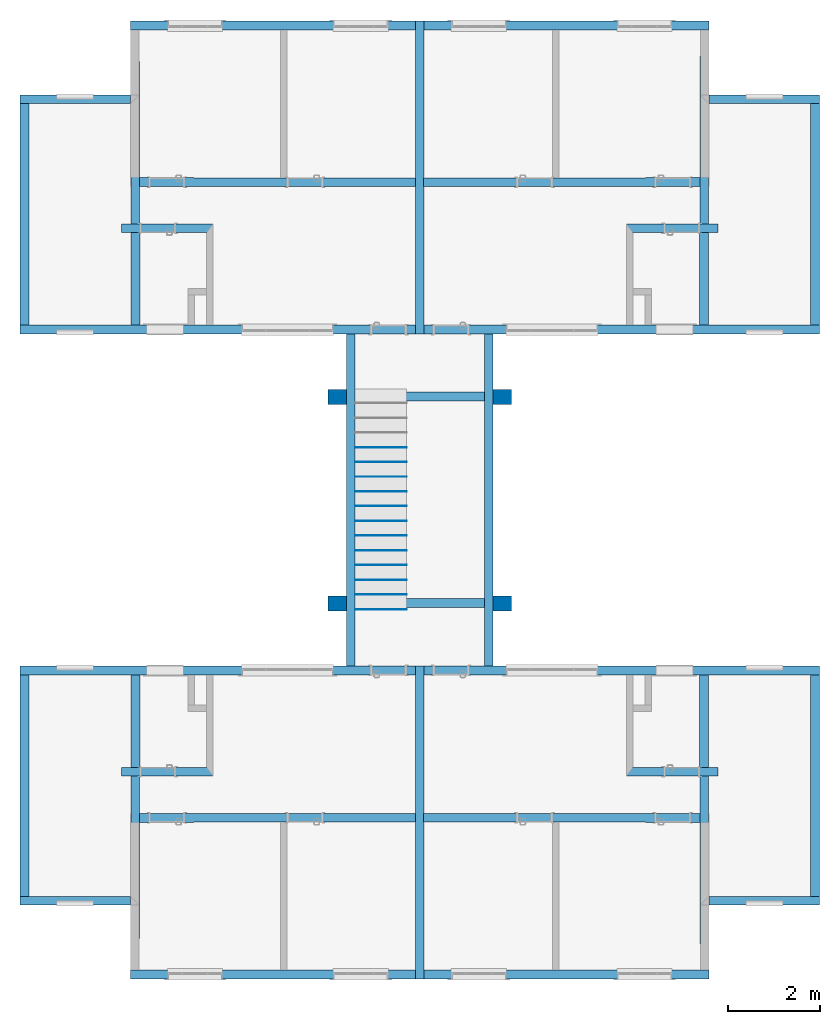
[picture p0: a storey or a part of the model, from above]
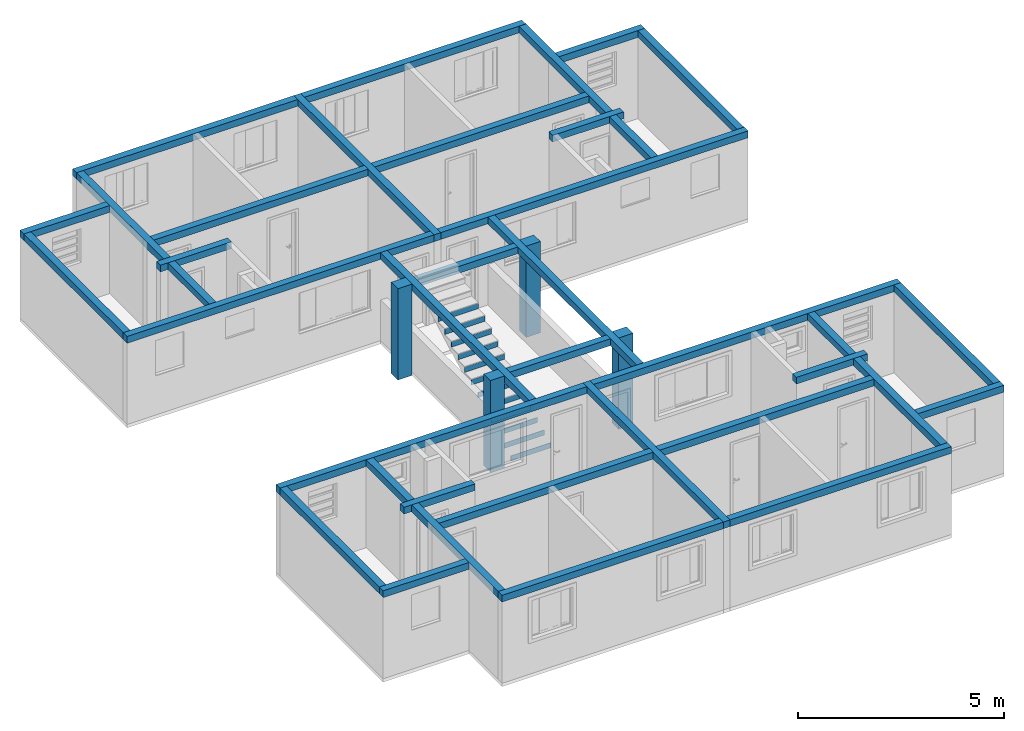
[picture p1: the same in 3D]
Properties of the parts of a building model (IFC2X3)

# File
Description: ViewDefinition [CoordinationView_V2.0, QuantityTakeOffAddOnView], Option [Elements to export: All elements on Current Story], Option [Partial Structure Display: Entire Model], Option [IFC Domain: All], Option [Structural Function: All Elements], Option [Convert Grid elements: On], Option [Convert IFC Annotations and Archicad 2D elements: Off], Option [Convert 2D symbols of Doors and Windows: Off], Option [Export geometries that Participates in Collision Detection only: Off], Option [Split complex elements: Off], Option [Material Preservation: Explode where necessary], Option [Elements in Solid Element Operations: Extruded/revolved], Option [Elements with junctions: Extruded/revolved without junctions], Option [IFC Model position: Survey Point and Project Origin], Option [Curtain Wall export mode: Container Element], Option [Railing export mode: Single Element], Option [Stair export mode: Container Element], Option [Properties To Export: All properties], Option [Space containment: Off], Option [Geometry to type objects: Off], Option [Element Properties: Visible Only], Option [Building Material Properties: Off], Option [Element Parameters: Off], Option [Component Parameters: All], Option [IFC Base Quantities: On], Option [Door Window Parameters: On], Option [IFC Space boundaries: Off], Option [Archicad Zone Categories as IFC Space classification data: Off], Option [Element Classifications: On]
File name: C:\Users\jplen\Downloads\Modelagem - Pavimento tipo (Plus).ifc
Time: 2024-05-23T11:48:52
Author: Architect
Organization: Building Designer Office
Written by: DDS_IFC v3.0
Made in: IFC file generated by Graphisoft Archicad 27.0.0 BRA FULL Windows version (IFC add-on version: 3001 BRA FULL).
Authorization: The authorising person

# IfcSite, Local
RefLatitude: -23, -32, 0, 0; RefLongitude: -46, -38, 0, 0; RefElevation: 0 mm
BaseQuantities - GrossPerimeter: 0 mm; GrossArea: 0 m2

# IfcBuilding, Construção
BaseQuantities - GrossFloorArea: 244.261 m2

# IfcBuildingStorey, Pavimento Tipo
In: Construção
Elevation: 0 mm
BaseQuantities - NetHeight: 2600 mm; GrossHeight: 2600 mm; Height: 2600 mm; GrossFloorArea: 244.261 m2

# IfcSpace: Circulação (2)
In: Pavimento Tipo
Type - ElementType: EXTERNAL; PredefinedType: USERDEFINED
InteriorOrExteriorSpace: INTERNAL
AC_Pset_RenovationAndPhasing - Renovation Status: Existing
BaseQuantities - Height: 2600 mm; FinishCeilingHeight: 2600 mm; FinishFloorHeight: 0 mm; ClearHeight: 2600 mm
Pset_SpaceCommon - Category: Circulação
Name | LongName | Classification | GrossFloorArea (m2) = NetFloorArea (m2) = SpaceNetFloorAreaBOMA (m2) = SpaceUsableFloorAreaBOMA (m2) = GrossCeilingArea (m2) = NetCeilingArea (m2) | GrossWallArea (m2) | NetWallArea (m2) | GrossPerimeter (mm) = NetPerimeter (mm) | GrossVolume (m3) = NetVolume (m3)
09 | Caixa de escada | Espaço Externo (Classificação Archicad); 4A 16 01 04 Escada (NBR 15965-6 4A) | 5.376 | 5.76 | 5.76 | 11840 | 13.9776
10 | Circulação Horizontal Externa | Espaço Externo (Classificação Archicad); 4A 16 04 04 Saguão (NBR 15965-6 4A) | 14.8841 | 25.032 | 18.312 | 22280 | 38.6987

# IfcSpace: Circulação (4)
In: Pavimento Tipo
Type - ElementType: INTERNAL; PredefinedType: USERDEFINED
LongName: Circulação; InteriorOrExteriorSpace: INTERNAL; Classification: Espaço Residencial (Classificação Archicad); 4A 19 04 10 Circulação (NBR 15965-6 4A)
Pset_SpaceCommon - Category: Circulação
AC_Pset_RenovationAndPhasing - Renovation Status: Existing
BaseQuantities - Height: 2600 mm; FinishCeilingHeight: 2600 mm; FinishFloorHeight: 0 mm; ClearHeight: 2600 mm; GrossFloorArea: 1.4565 m2; NetFloorArea: 1.4565 m2; SpaceNetFloorAreaBOMA: 1.4565 m2; SpaceUsableFloorAreaBOMA: 1.4565 m2; GrossCeilingArea: 1.4565 m2; NetCeilingArea: 1.4565 m2; GrossWallArea: 4.29812 m2; NetWallArea: 2.61812 m2; GrossPerimeter: 5209.26 mm; NetPerimeter: 5209.26 mm; GrossVolume: 3.7869 m3; NetVolume: 3.78689 m3
Name
Apartamento 1 - 13
Apartamento 2 - 13
Apartamento 3 - 13
Apartamento 4 - 13

# IfcSpace: Área privativa (4)
In: Pavimento Tipo
LongName: Banheiro; InteriorOrExteriorSpace: INTERNAL; Classification: 4A 19 04 07 Banheiro residencial (NBR 15965-6 4A)
Pset_SpaceCommon - Category: Área privativa
AC_Pset_RenovationAndPhasing - Renovation Status: Existing
BaseQuantities - Height: 2600 mm; FinishCeilingHeight: 2600 mm; FinishFloorHeight: 0 mm; ClearHeight: 2600 mm; GrossFloorArea: 2.6146 m2; NetFloorArea: 2.6146 m2; SpaceNetFloorAreaBOMA: 2.6146 m2; SpaceUsableFloorAreaBOMA: 2.6146 m2; GrossCeilingArea: 2.6146 m2; NetCeilingArea: 2.6146 m2; GrossWallArea: 12.3731 m2; NetWallArea: 10.2131 m2; GrossPerimeter: 6940 mm; NetPerimeter: 6940 mm; GrossVolume: 6.79796 m3; NetVolume: 6.79796 m3
Name
Apartamento 1 - 06
Apartamento 2 - 06
Apartamento 3 - 06
Apartamento 4 - 06

# IfcSpace: Área privativa (16)
In: Pavimento Tipo
Type - ElementType: INTERNAL; PredefinedType: USERDEFINED
InteriorOrExteriorSpace: INTERNAL
Pset_SpaceCommon - Category: Área privativa
AC_Pset_RenovationAndPhasing - Renovation Status: Existing
BaseQuantities - Height: 2600 mm; FinishCeilingHeight: 2600 mm; FinishFloorHeight: 0 mm; ClearHeight: 2600 mm
Name | LongName | Classification | GrossFloorArea (m2) = NetFloorArea (m2) = SpaceNetFloorAreaBOMA (m2) = SpaceUsableFloorAreaBOMA (m2) = GrossCeilingArea (m2) = NetCeilingArea (m2) | GrossWallArea (m2) | NetWallArea (m2) | GrossPerimeter (mm) = NetPerimeter (mm) | GrossVolume (m3) = NetVolume (m3)
Apartamento 1 - 12 | Sala de estar | Espaço Residencial (Classificação Archicad); 4A 19 01 07 Sala de Estar (NBR 15965-6 4A) | 13.2704 | 26.7962 | 21.0362 | 14836.1 | 34.5031
Apartamento 1 - 04 | Quarto 01 | 4A 19 01 01 Dormitório (NBR 15965-6 4A); Espaço Residencial (Classificação Archicad) | 8.96458 | 21.7672 | 18.6681 | 12005.8 | 23.3079
Apartamento 1 - 14 | Cozinha | Espaço Residencial (Classificação Archicad); 4A 19 01 25 Cozinha (NBR 15965-6 4A) | 10.5869 | 23.5579 | 21.9579 | 14435.8 | 27.5258
Apartamento 1 - 05 | Quarto 02 | 4A 19 01 01 Dormitório (NBR 15965-6 4A); Espaço Residencial (Classificação Archicad) | 9.85631 | 31.74 | 28.62 | 12941 | 25.6264
Apartamento 2 - 12 | Sala de estar | Espaço Residencial (Classificação Archicad); 4A 19 01 07 Sala de Estar (NBR 15965-6 4A) | 13.2704 | 26.7962 | 21.0362 | 14836.1 | 34.5031
Apartamento 2 - 04 | Quarto 01 | 4A 19 01 01 Dormitório (NBR 15965-6 4A); Espaço Residencial (Classificação Archicad) | 8.96458 | 21.7672 | 18.6681 | 12005.8 | 23.3079
Apartamento 2 - 05 | Quarto 02 | 4A 19 01 01 Dormitório (NBR 15965-6 4A); Espaço Residencial (Classificação Archicad) | 9.85631 | 31.702 | 28.582 | 12941 | 25.6264
Apartamento 2 - 14 | Cozinha | Espaço Residencial (Classificação Archicad); 4A 19 01 25 Cozinha (NBR 15965-6 4A) | 10.5869 | 23.5579 | 21.9579 | 14435.8 | 27.5258
Apartamento 3 - 12 | Sala de estar | Espaço Residencial (Classificação Archicad); 4A 19 01 07 Sala de Estar (NBR 15965-6 4A) | 13.2704 | 26.7962 | 21.0362 | 14836.1 | 34.5031
Apartamento 3 - 04 | Quarto 01 | 4A 19 01 01 Dormitório (NBR 15965-6 4A); Espaço Residencial (Classificação Archicad) | 8.96458 | 21.7672 | 18.6681 | 12005.8 | 23.3079
Apartamento 3 - 14 | Cozinha | Espaço Residencial (Classificação Archicad); 4A 19 01 25 Cozinha (NBR 15965-6 4A) | 10.5869 | 23.5579 | 21.9579 | 14435.8 | 27.5258
Apartamento 3 - 05 | Quarto 02 | 4A 19 01 01 Dormitório (NBR 15965-6 4A); Espaço Residencial (Classificação Archicad) | 9.85631 | 31.74 | 28.62 | 12941 | 25.6264
Apartamento 4 - 12 | Sala de estar | Espaço Residencial (Classificação Archicad); 4A 19 01 07 Sala de Estar (NBR 15965-6 4A) | 13.2704 | 26.7962 | 21.0362 | 14836.1 | 34.5031
Apartamento 4 - 04 | Quarto 01 | 4A 19 01 01 Dormitório (NBR 15965-6 4A); Espaço Residencial (Classificação Archicad) | 8.96458 | 21.7672 | 18.6681 | 12005.8 | 23.3079
Apartamento 4 - 14 | Cozinha | Espaço Residencial (Classificação Archicad); 4A 19 01 25 Cozinha (NBR 15965-6 4A) | 10.5869 | 23.5579 | 21.9579 | 14435.8 | 27.5258
Apartamento 4 - 05 | Quarto 02 | 4A 19 01 01 Dormitório (NBR 15965-6 4A); Espaço Residencial (Classificação Archicad) | 9.85631 | 31.702 | 28.582 | 12941 | 25.6264

# IfcSpace: Área técnica (4)
In: Pavimento Tipo
Type - ElementType: INTERNAL; PredefinedType: USERDEFINED
LongName: Shaft do banheiro; InteriorOrExteriorSpace: INTERNAL; Classification: Espaço Residencial (Classificação Archicad); 4A 13 01 13 22 Shaft de Distribuição de Hidráulica (NBR 15965-6 4A)
Pset_SpaceCommon - Category: Área técnica
AC_Pset_RenovationAndPhasing - Renovation Status: Existing
BaseQuantities - Height: 2600 mm; FinishCeilingHeight: 2600 mm; FinishFloorHeight: 0 mm; ClearHeight: 2600 mm; GrossFloorArea: 0.1716 m2; NetFloorArea: 0.1716 m2; SpaceNetFloorAreaBOMA: 0.1716 m2; SpaceUsableFloorAreaBOMA: 0.1716 m2; GrossCeilingArea: 0.1716 m2; NetCeilingArea: 0.1716 m2; GrossWallArea: 4.732 m2; NetWallArea: 4.732 m2; GrossPerimeter: 1840 mm; NetPerimeter: 1840 mm; GrossVolume: 0.44616 m3; NetVolume: 0.44616 m3
Name
Apartamento 1 - 11
Apartamento 2 - 11
Apartamento 3 - 11
Apartamento 4 - 11

# IfcBeam: Concreto - Estrutural 190 x 200 (38)
In: Pavimento Tipo
Type - PredefinedType: BEAM
Classification: 3E 12 06 02 00 Viga (NBR 15965-5 3E); Viga (Classificação Archicad); Material: Concreto - Estrutural
Pset_ManufacturerTypeInformation - ProductionYear: DD/MM/YYYY
Pset_BeamCommon - LoadBearing: yes; Reference: Concreto - Estrutural 190 x 200
Component Properties - Concreto - Estrutural, Tipo de Componente: Núcleo
AC_Pset_RenovationAndPhasing - Renovation Status: Existing
BaseQuantities - Width: 190 mm; Depth: 200 mm; CrossSectionArea: 0.038 m2
Component Quantities - Concreto - Estrutural, Espessura do Componente: 190 mm; Concreto - Estrutural, Altura do Componente Retangular: 200 mm; Concreto - Estrutural, Largura do Componente Retangular: 190 mm; Concreto - Estrutural, Área de Seção Transversal do Componente: 0.038 m2
Name | Description | IsExternal | Concreto - Estrutural, Carbono Incorporado | Concreto - Estrutural, Energia Incorporada (MJ) | NetSurfaceAreaExtrudedSides (m2) = OuterSurfaceArea (m2) | Length (mm) | TotalSurfaceArea (m2) = GrossSurfaceArea (m2) = NetSurfaceArea (m2) | GrossVolume (m3) | NetVolume (m3) = Concreto - Estrutural, Volume Componente (Líquido) (m3) = Concreto - Estrutural, Volume do componente (Bruto) (m3) = Concreto - Estrutural, Volume Componente (Condicional) (m3) | Concreto - Estrutural, Massa (kg) | Concreto - Estrutural, Área de Componente Projetada (Líquida) (m2) = Concreto - Estrutural, Área de Componente Projetada (Bruta) (m2)
Apartamento 1 - V03 | Viga-externa-inloco-concreto_armado-19cm x 20cm | yes | 41.4885 (kgCO₂) | 402.313 | 1.87002 | 2397.46 | 1.94602 | 0.0911034 | 0.0911034 | 209.538 | 0.479492
Apartamento 1 - V01 | Viga-externa-inloco-concreto_armado-19cm x 20cm | yes | 148.568 (kgCO₂) | 1440.66 | 6.69645 | 8585.19 | 6.77245 | 0.333457 | 0.326237 | 750.346 | 1.71704
Apartamento 1 - V05 | Viga-externa-inloco-concreto_armado-19cm x 20cm | yes | 107.073 (kgCO₂) | 1038.28 | 4.82612 | 6187.33 | 4.90212 | 0.242339 | 0.235119 | 540.773 | 1.23747
Apartamento 1 - V04 | Viga-externa-inloco-concreto_armado-19cm x 20cm | yes | 72.9091 (kgCO₂) | 706.997 | 3.32416 | 4403.36 | 3.40016 | 0.174531 | 0.160099 | 368.228 | 0.880671
Apartamento 1 - V08 | Viga-interna-inloco-concreto_armado-19cm x 20cm | no | 34.4373 (kgCO₂) | 333.938 | 1.5522 | 1990 | 1.6282 | 0.07562 | 0.07562 | 173.926 | 0.398
Apartamento 1 - V02 | Viga-externa-inloco-concreto_armado-19cm x 20cm | yes | 83.238 (kgCO₂) | 807.156 | 3.7518 | 4810 | 3.8278 | 0.19 | 0.18278 | 420.394 | 0.962
Apartamento 1 - V09 | Viga-interna-inloco-concreto_armado-19cm x 20cm | no | 34.7834 (kgCO₂) | 337.294 | 1.5678 | 2010 | 1.6438 | 0.0836 | 0.07638 | 175.674 | 0.402
Apartamento 1 - V07 | Viga-interna-inloco-concreto_armado-19cm x 20cm | no | 103.652 (kgCO₂) | 1005.11 | 4.67194 | 5989.94 | 4.74794 | 0.228153 | 0.227607 | 523.497 | 1.19799
Apartamentos 1 e 2 - V06 | Viga-interna-inloco-concreto_armado-19cm x 20cm |  | 117.413 (kgCO₂) | 1138.55 | 5.25739 | 6792.9 | 5.33339 | 0.25813 | 0.257823 | 592.993 | 1.35858
Apartamento 2 - V03 | Viga-externa-inloco-concreto_armado-19cm x 20cm | yes | 41.4885 (kgCO₂) | 402.313 | 1.87002 | 2397.46 | 1.94602 | 0.0911034 | 0.0911034 | 209.538 | 0.479492
Apartamento 2 - V05 | Viga-externa-inloco-concreto_armado-19cm x 20cm | yes | 107.073 (kgCO₂) | 1038.28 | 4.82612 | 6187.33 | 4.90212 | 0.235119 | 0.235119 | 540.773 | 1.23747
Apartamento 2 - V01 | Viga-externa-inloco-concreto_armado-19cm x 20cm | yes | 148.568 (kgCO₂) | 1440.66 | 6.69645 | 8585.19 | 6.77245 | 0.326237 | 0.326237 | 750.346 | 1.71704
Apartamento 2 - V04 | Viga-externa-inloco-concreto_armado-19cm x 20cm | yes | 72.9091 (kgCO₂) | 706.997 | 3.32416 | 4403.36 | 3.40016 | 0.174531 | 0.160099 | 368.228 | 0.880671
Apartamento 2 - V09 | Viga-interna-inloco-concreto_armado-19cm x 20cm | no | 34.7834 (kgCO₂) | 337.294 | 1.5678 | 2010 | 1.6438 | 0.0836 | 0.07638 | 175.674 | 0.402
Apartamento 2 - V02 | Viga-externa-inloco-concreto_armado-19cm x 20cm | yes | 83.238 (kgCO₂) | 807.156 | 3.7518 | 4810 | 3.8278 | 0.19 | 0.18278 | 420.394 | 0.962
Apartamento 2 - V07 | Viga-interna-inloco-concreto_armado-19cm x 20cm | no | 103.792 (kgCO₂) | 1006.47 | 4.67824 | 5998 | 4.75424 | 0.228153 | 0.227914 | 524.203 | 1.1996
Apartamento 4 - V02 | Viga-externa-inloco-concreto_armado-19cm x 20cm | yes | 83.238 (kgCO₂) | 807.156 | 3.7518 | 4810 | 3.8278 | 0.19 | 0.18278 | 420.394 | 0.962
Apartamento 4 - V09 | Viga-interna-inloco-concreto_armado-19cm x 20cm | no | 34.7834 (kgCO₂) | 337.294 | 1.5678 | 2010 | 1.6438 | 0.0836 | 0.07638 | 175.674 | 0.402
Apartamento 4 - V08 | Viga-interna-inloco-concreto_armado-19cm x 20cm | no | 34.4373 (kgCO₂) | 333.938 | 1.5522 | 1990 | 1.6282 | 0.07562 | 0.07562 | 173.926 | 0.398
Apartamento 4 - V07 | Viga-interna-inloco-concreto_armado-19cm x 20cm | no | 103.792 (kgCO₂) | 1006.47 | 4.67824 | 5998 | 4.75424 | 0.228153 | 0.227914 | 524.203 | 1.1996
Apartamento 2 - V08 | Viga-interna-inloco-concreto_armado-19cm x 20cm | no | 34.4373 (kgCO₂) | 333.938 | 1.5522 | 1990 | 1.6282 | 0.07562 | 0.07562 | 173.926 | 0.398
Apartamento 3 - V03 | Viga-externa-inloco-concreto_armado-19cm x 20cm | yes | 41.4885 (kgCO₂) | 402.313 | 1.87002 | 2397.46 | 1.94602 | 0.0911034 | 0.0911034 | 209.538 | 0.479492
Apartamento 3 - V01 | Viga-externa-inloco-concreto_armado-19cm x 20cm | yes | 148.568 (kgCO₂) | 1440.66 | 6.69645 | 8585.19 | 6.77245 | 0.333457 | 0.326237 | 750.346 | 1.71704
Apartamento 3 - V05 | Viga-externa-inloco-concreto_armado-19cm x 20cm | yes | 107.073 (kgCO₂) | 1038.28 | 4.82612 | 6187.33 | 4.90212 | 0.242339 | 0.235119 | 540.773 | 1.23747
Apartamento 3 - V08 | Viga-interna-inloco-concreto_armado-19cm x 20cm | no | 34.4373 (kgCO₂) | 333.938 | 1.5522 | 1990 | 1.6282 | 0.07562 | 0.07562 | 173.926 | 0.398
Apartamento 3 - V02 | Viga-externa-inloco-concreto_armado-19cm x 20cm | yes | 83.238 (kgCO₂) | 807.156 | 3.7518 | 4810 | 3.8278 | 0.19 | 0.18278 | 420.394 | 0.962
Apartamento 3 - V09 | Viga-interna-inloco-concreto_armado-19cm x 20cm | no | 34.7834 (kgCO₂) | 337.294 | 1.5678 | 2010 | 1.6438 | 0.0836 | 0.07638 | 175.674 | 0.402
Apartamento 3 - V04 | Viga-externa-inloco-concreto_armado-19cm x 20cm | yes | 72.9091 (kgCO₂) | 706.997 | 3.32416 | 4403.36 | 3.40016 | 0.174531 | 0.160099 | 368.228 | 0.880671
Apartamento 3 - V07 | Viga-interna-inloco-concreto_armado-19cm x 20cm | no | 103.652 (kgCO₂) | 1005.11 | 4.67194 | 5989.94 | 4.74794 | 0.228153 | 0.227607 | 523.497 | 1.19799
Apartamentos 3 e 4 - V06 | Viga-interna-inloco-concreto_armado-19cm x 20cm |  | 117.413 (kgCO₂) | 1138.55 | 5.25739 | 6792.9 | 5.33339 | 0.25813 | 0.257823 | 592.993 | 1.35858
Apartamento 4 - V03 | Viga-externa-inloco-concreto_armado-19cm x 20cm | yes | 41.4885 (kgCO₂) | 402.313 | 1.87002 | 2397.46 | 1.94602 | 0.0911034 | 0.0911034 | 209.538 | 0.479492
Apartamento 4 - V01 | Viga-externa-inloco-concreto_armado-19cm x 20cm | yes | 148.568 (kgCO₂) | 1440.66 | 6.69645 | 8585.19 | 6.77245 | 0.326237 | 0.326237 | 750.346 | 1.71704
Apartamento 4 - V05 | Viga-externa-inloco-concreto_armado-19cm x 20cm | yes | 107.073 (kgCO₂) | 1038.28 | 4.82612 | 6187.33 | 4.90212 | 0.235119 | 0.235119 | 540.773 | 1.23747
Apartamento 4 - V04 | Viga-externa-inloco-concreto_armado-19cm x 20cm | yes | 72.9091 (kgCO₂) | 706.997 | 3.32416 | 4403.36 | 3.40016 | 0.174531 | 0.160099 | 368.228 | 0.880671
2 x NúcleoV03 | Viga-externa-inloco-concreto_armado-19cm x 20cm |  | 48.6276 (kgCO₂) | 471.54 | 2.1918 | 2810 | 2.2678 | 0.114 | 0.10678 | 245.594 | 0.562
2 x NúcleoV03 | Viga-externa-inloco-concreto_armado-19cm x 20cm |  | 124.77 (kgCO₂) | 1209.9 | 5.6238 | 7210 | 5.6998 | 0.27398 | 0.27398 | 630.154 | 1.442

# IfcColumn: Concreto Armado - Estrutural 400 x 320 (4)
In: Pavimento Tipo
Type - PredefinedType: COLUMN
Classification: Pilar (Classificação Archicad); 3E 12 10 02 02 Pilar (NBR 15965-5 3E); Material: Concreto Armado - Estrutural
Pset_ManufacturerTypeInformation - ProductionYear: DD/MM/YYYY
AC_Pset_RenovationAndPhasing - Renovation Status: Existing
Pset_ColumnCommon - LoadBearing: yes; Reference: Concreto Armado - Estrutural 400 x 320
Component Properties - Concreto Armado - Estrutural, Tipo de Componente: Núcleo
Component Quantities - Concreto Armado - Estrutural, Espessura do Componente: 400 mm; Concreto Armado - Estrutural, Altura do Componente Retangular: 320 mm; Concreto Armado - Estrutural, Largura do Componente Retangular: 400 mm; Concreto Armado - Estrutural, Área de Seção Transversal do Componente: 0.128 m2
BaseQuantities - Width: 400 mm; Depth: 320 mm; CrossSectionArea: 0.128 m2
Name | Concreto Armado - Estrutural, Carbono Incorporado | Concreto Armado - Estrutural, Energia Incorporada (MJ) | Concreto Armado - Estrutural, Massa (kg) | Concreto Armado - Estrutural, Volume Componente (Líquido) (m3) = Concreto Armado - Estrutural, Volume do componente (Bruto) (m3) = GrossVolume (m3) = NetVolume (m3) | Length (mm) | OuterSurfaceArea (m2) | TotalSurfaceArea (m2) = GrossSurfaceArea (m2)
NúcleoP02 | 200.724 (kgCO₂) | 1932.6 | 829.44 | 0.3456 | 2700 | 3.888 | 4.144
NúcleoP01 | 200.724 (kgCO₂) | 1932.6 | 829.44 | 0.3456 | 2700 | 3.888 | 4.144
NúcleoP03 | 200.887 (kgCO₂) | 1934.16 | 830.11 | 0.345879 | 2702.18 | 3.89114 | 4.14714
NúcleoP04 | 200.887 (kgCO₂) | 1934.16 | 830.11 | 0.345879 | 2702.18 | 3.89114 | 4.14714

# IfcDoor: Porta 27 (8)
In: Pavimento Tipo
Type - OperationType: SINGLE_SWING_LEFT; ParameterTakesPrecedence: no; Sizeable: no
Type - Door Lining Properties - LiningThickness: 50 mm; CasingThickness: 70 mm; CasingDepth: 19 mm
Type - Door Panel Properties - Panel 1 - PanelDepth: 30 mm; PanelOperation: SWINGING; PanelWidth: 1; PanelPosition: MIDDLE
OverallHeight: 2100 mm; OverallWidth: 800 mm; Classification: Porta (Classificação Archicad); 3E 20 02 02 04 Porta de girar (NBR 15965-5 3E)
Pset_DoorCommon - ThermalTransmittance: 0; IsExternal: no
AC_Pset_RenovationAndPhasing - Renovation Status: Existing
BaseQuantities - Height: 2100 mm; Width: 800 mm; Perimeter: 5800 mm; Area: 1.68 m2; Volume: 0.10295 m3; Depth: 190 mm; NetVolume: 0.10295 m3
Component Quantities - Component, Volume Componente (Líquido): 0.10295 m3; Component, Volume do componente (Bruto): 0.10295 m3
Name | Description
Apartamento 1 - P01 | Porta-externa-genérico-madeira-girar-80cm x 210cm
Apartamento 1 - P02 | Porta-interna-genérico-madeira-girar-80cm x 210cm
Apartamento 2 - P04 | Porta-interna-genérico-madeira-girar-80cm x 210cm
Apartamento 2 - P03 | Porta-interna-genérico-madeira-girar-80cm x 210cm
Apartamento 3 - P01 | Porta-externa-genérico-madeira-girar-80cm x 210cm
Apartamento 3 - P02 | Porta-interna-genérico-madeira-girar-80cm x 210cm
Apartamento 4 - P04 | Porta-interna-genérico-madeira-girar-80cm x 210cm
Apartamento 4 - P03 | Porta-interna-genérico-madeira-girar-80cm x 210cm

# IfcDoor: Porta 27 (8)
In: Pavimento Tipo
Type - OperationType: SINGLE_SWING_RIGHT; ParameterTakesPrecedence: no; Sizeable: no
Type - Door Lining Properties - LiningThickness: 50 mm; CasingThickness: 70 mm; CasingDepth: 19 mm
Type - Door Panel Properties - Panel 1 - PanelDepth: 30 mm; PanelOperation: SWINGING; PanelWidth: 1; PanelPosition: MIDDLE
OverallHeight: 2100 mm; OverallWidth: 800 mm; Classification: Porta (Classificação Archicad); 3E 20 02 02 04 Porta de girar (NBR 15965-5 3E)
Pset_DoorCommon - ThermalTransmittance: 0; IsExternal: no
AC_Pset_RenovationAndPhasing - Renovation Status: Existing
BaseQuantities - Height: 2100 mm; Width: 800 mm; Perimeter: 5800 mm; Area: 1.68 m2; Volume: 0.10295 m3; Depth: 190 mm; NetVolume: 0.10295 m3
Component Quantities - Component, Volume Componente (Líquido): 0.10295 m3; Component, Volume do componente (Bruto): 0.10295 m3
Name | Description
Apartamento 1 - P03 | Porta-interna-genérico-madeira-girar-80cm x 210cm
Apartamento 1 - P04 | Porta-interna-genérico-madeira-girar-80cm x 210cm
Apartamento 2 - P01 | Porta-externa-genérico-madeira-girar-80cm x 210cm
Apartamento 2 - P02 | Porta-interna-genérico-madeira-girar-80cm x 210cm
Apartamento 3 - P04 | Porta-interna-genérico-madeira-girar-80cm x 210cm
Apartamento 3 - P03 | Porta-interna-genérico-madeira-girar-80cm x 210cm
Apartamento 4 - P01 | Porta-externa-genérico-madeira-girar-80cm x 210cm
Apartamento 4 - P02 | Porta-interna-genérico-madeira-girar-80cm x 210cm

# IfcMember: IfcMember (15)
In: Pavimento Tipo
Type - ElementType: Stair Riser; PredefinedType: USERDEFINED
Classification: Espelho de Escada (Classificação Archicad); Material: Madeira
AC_Pset_RenovationAndPhasing - Renovation Status: Existing
Component Properties - Madeira, Carbono Incorporado: 0.270816 (kgCO₂); Madeira, Energia Incorporada: 6.19752 MJ
Component Quantities - Madeira, Massa: 0.5208 kg; Madeira, Volume Componente (Líquido): 0.001736 m3; Madeira, Volume do componente (Bruto): 0.001736 m3
BaseQuantities - GrossVolume: 0.001736 m3; NetVolume: 0.001736 m3

# IfcMember: IfcMember (15)
In: Pavimento Tipo
Type - ElementType: Stair Tread; PredefinedType: USERDEFINED
Classification: Piso de Escada (Classificação Archicad); Material: Madeira
AC_Pset_RenovationAndPhasing - Renovation Status: Existing
Name | Madeira, Carbono Incorporado | Madeira, Energia Incorporada (MJ) | GrossVolume (m3) = NetVolume (m3) = Madeira, Volume Componente (Líquido) (m3) = Madeira, Volume do componente (Bruto) (m3) | Madeira, Massa (kg)
14 x NúcleoPiso Esc. - 017 | 1.49168 (kgCO₂) | 34.1366 | 0.00956207 | 2.86862
NúcleoPiso Esc. - 017 | 1.38248 (kgCO₂) | 31.6376 | 0.00886207 | 2.65862

# IfcOpeningElement (40)
In: Pavimento Tipo
BaseQuantities - Depth: 190 mm
Name | Height (mm) | Width (mm) | Area (m2) | Volume (m3)
Apartamento 1 - J04 | 1000 | 800 | 0.8 | 0.0194095
Apartamento 1 - J06 | 1200 | 1200 | 1.44 | 0.049487
Apartamento 1 - J05 | 1200 | 1200 | 1.44 | 0.049487
Apartamento 1 - J03 | 1000 | 800 | 0.8 | 0.0194095
Apartamento 1 - J02 | 600 | 800 | 0.48 | 0.0253701
Apartamento 1 - J01 | 1200 | 2000 | 2.4 | 0.0645128
Apartamento 1 - P01 | 2100 | 800 | 1.68 | 0.10295
Apartamento 1 - P03 | 2100 | 800 | 1.68 | 0.10295
Apartamento 1 - P04 | 2100 | 800 | 1.68 | 0.10295
Apartamento 1 - P02 | 2100 | 800 | 1.68 | 0.10295
Apartamento 2 - J04 | 1000 | 800 | 0.8 | 0.0194095
Apartamento 2 - J06 | 1200 | 1200 | 1.44 | 0.049487
Apartamento 2 - J05 | 1200 | 1200 | 1.44 | 0.049487
Apartamento 2 - J03 | 1000 | 800 | 0.8 | 0.0194095
Apartamento 2 - J02 | 600 | 800 | 0.48 | 0.0253701
Apartamento 2 - P01 | 2100 | 800 | 1.68 | 0.10295
Apartamento 2 - J01 | 1200 | 2000 | 2.4 | 0.0645128
Apartamento 2 - P03 | 2100 | 800 | 1.68 | 0.10295
Apartamento 2 - P04 | 2100 | 800 | 1.68 | 0.10295
Apartamento 2 - P02 | 2100 | 800 | 1.68 | 0.10295
Apartamento 3 - J04 | 1000 | 800 | 0.8 | 0.0194095
Apartamento 3 - J06 | 1200 | 1200 | 1.44 | 0.049487
Apartamento 3 - J05 | 1200 | 1200 | 1.44 | 0.049487
Apartamento 3 - J03 | 1000 | 800 | 0.8 | 0.0194095
Apartamento 3 - J02 | 600 | 800 | 0.48 | 0.0253701
Apartamento 3 - P01 | 2100 | 800 | 1.68 | 0.10295
Apartamento 3 - J01 | 1200 | 2000 | 2.4 | 0.0645128
Apartamento 3 - P03 | 2100 | 800 | 1.68 | 0.10295
Apartamento 3 - P04 | 2100 | 800 | 1.68 | 0.10295
Apartamento 3 - P02 | 2100 | 800 | 1.68 | 0.10295
Apartamento 4 - J04 | 1000 | 800 | 0.8 | 0.0194095
Apartamento 4 - J05 | 1200 | 1200 | 1.44 | 0.049487
Apartamento 4 - J06 | 1200 | 1200 | 1.44 | 0.049487
Apartamento 4 - J03 | 1000 | 800 | 0.8 | 0.0194095
Apartamento 4 - J02 | 600 | 800 | 0.48 | 0.0253701
Apartamento 4 - J01 | 1200 | 2000 | 2.4 | 0.0645128
Apartamento 4 - P01 | 2100 | 800 | 1.68 | 0.10295
Apartamento 4 - P03 | 2100 | 800 | 1.68 | 0.10295
Apartamento 4 - P04 | 2100 | 800 | 1.68 | 0.10295
Apartamento 4 - P02 | 2100 | 800 | 1.68 | 0.10295

# IfcSlab: Concreto 100 (7)
In: Pavimento Tipo
Description: Laje-interna-inloco-concreto_armado-10cm; Classification: Laje (Classificação Archicad); 3E 12 06 08 Laje (NBR 15965-5 3E); Material: Concreto 100 mm
AC_Pset_RenovationAndPhasing - Renovation Status: Existing
Component Properties - Concreto, Tipo de Componente: Nenhum
BaseQuantities - Width: 100 mm
Component Quantities - Concreto, Espessura do Componente: 100 mm
Pset_ManufacturerTypeInformation - ProductionYear: DD/MM/YYYY
Pset_SlabCommon - LoadBearing: yes
Name | Concreto, Carbono Incorporado | Concreto, Energia Incorporada (MJ) | Perimeter (mm) | GrossArea (m2) = Concreto, Área de Componente Projetada (Bruta) (m2) | NetArea (m2) = Concreto, Área de Componente Projetada (Líquida) (m2) = Concreto, Área de Componente Projetada (Condicional) (m2) | GrossVolume (m3) = Concreto, Volume do componente (Bruto) (m3) = Concreto, Volume Componente (Condicional) (m3) | NetVolume (m3) = Concreto, Volume Componente (Líquido) (m3) | Concreto, Massa (kg) | IsExternal
Apartamento 1 - L04 | 1049.14 (kgCO₂) | 7255.75 | 30755.3 | 54.4726 | 54.4726 | 5.44726 | 5.44726 | 9805.07 | no
Apartamentos 1 e 2 - L06 | 24.8587 (kgCO₂) | 171.92 | 13966.2 | 1.29069 | 1.29069 | 0.129069 | 0.129069 | 232.324 | no
Apartamento 2 - L04 | 1049.14 (kgCO₂) | 7255.75 | 30755.3 | 54.4726 | 54.4726 | 5.44726 | 5.44726 | 9805.07 | no
Apartamento 3 - L04 | 1049.14 (kgCO₂) | 7255.75 | 30755.3 | 54.4726 | 54.4726 | 5.44726 | 5.44726 | 9805.07 | no
Apartamentos 3 e 4 - L06 | 24.8587 (kgCO₂) | 171.92 | 13966.2 | 1.29069 | 1.29069 | 0.129069 | 0.129069 | 232.324 | no
Apartamento 4 - L04 | 1049.14 (kgCO₂) | 7255.75 | 30755.3 | 54.4726 | 54.4726 | 5.44726 | 5.44726 | 9805.07 | no
NúcleoL05 | 365.106 (kgCO₂) | 2525.03 | 20800 | 22.9999 | 18.9567 | 2.29999 | 1.89567 | 3412.21

# IfcStair, NúcleoEscada - 001
In: Pavimento Tipo
Classification: 3E 08 06 04 Escada (NBR 15965-5 3E); Escada (Classificação Archicad)
Pset_StairCommon - NumberOfRiser: 15; NumberOfTreads: 15; RiserHeight: 180 mm; RequiredHeadroom: 2200 mm
AC_Pset_RenovationAndPhasing - Renovation Status: Existing
BaseQuantities - Length: 4800 mm; Height: 2700 mm; GrossVolume: 1.24656 m3; NetVolume: 1.24656 m3

# IfcStairFlight: IfcStairFlight, NúcleoLance - 002
In: Pavimento Tipo
Classification: Lance de Escada (Classificação Archicad); Material: Concreto - Estrutural
AC_Pset_RenovationAndPhasing - Renovation Status: Existing
Component Quantities - Concreto - Estrutural, Massa: 2478.92 kg; Concreto - Estrutural, Volume Componente (Líquido): 1.07779 m3; Concreto - Estrutural, Volume do componente (Bruto): 1.07779 m3
Component Properties - Concreto - Estrutural, Carbono Incorporado: 490.826 (kgCO₂); Concreto - Estrutural, Energia Incorporada: 4759.53 MJ

# IfcWallStandardCase: Concreto - Estrutural 190 (40)
In: Pavimento Tipo
Classification: 3E 14 02 00 Parede (NBR 15965-5 3E); Parede (Classificação Archicad); Material: Concreto - Estrutural 190 mm
Pset_WallCommon - AcousticRating: 0,00
AC_Pset_RenovationAndPhasing - Renovation Status: Existing
Component Properties - Concreto - Estrutural, Tipo de Componente: Nenhum
BaseQuantities - Width: 190 mm
Component Quantities - Concreto - Estrutural, Espessura do Componente: 190 mm; Concreto - Estrutural, Largura do Componente Retangular: 190 mm
Name | Description | IsExternal | LoadBearing | Concreto - Estrutural, Carbono Incorporado | Concreto - Estrutural, Energia Incorporada (MJ) | Length (mm) | Height (mm) | GrossFootprintArea (m2) = NetFootprintArea (m2) | GrossSideArea (m2) | NetSideArea (m2) | GrossVolume (m3) | NetVolume (m3) | Concreto - Estrutural, Massa (kg) | Concreto - Estrutural, Área de Componente Projetada (Líquida) (m2) | Concreto - Estrutural, Área de Componente Projetada (Bruta) (m2) | Concreto - Estrutural, Área de Componente Projetada (Condicional) (m2) | Concreto - Estrutural, Altura do Componente Retangular (mm) | Concreto - Estrutural, Área de Seção Transversal do Componente (m2) | Concreto - Estrutural, Volume Componente (Líquido) (m3) | Concreto - Estrutural, Volume do componente (Bruto) (m3) = Concreto - Estrutural, Volume Componente (Condicional) (m3)
Apartamento 1 - Parede-003 | Parede-externa-inloco-bloco_concreto-estrutural-19cm | yes | yes | 427.772 (kgCO₂) | 4148.1 | 2397.46 | 2600 | 0.455517 | 5.7546 | 4.9426 | 1.09337 | 0.939333 | 2160.47 | 4.95464 | 5.75464 | 5.75464 | 2600 | 0.494 | 0.939334 | 1.09337
Apartamento 1 - Parede-078 | Parede-interna-inloco-bloco_concreto-estrutural-19cm | no | yes | 334.56 (kgCO₂) | 3244.22 | 1702.17 | 2600 | 0.305362 | 4.01792 | 4.01792 | 0.73465 | 0.734651 | 1689.7 | 4.17871 | 4.17871 | 4.17871 | 2600 | 0.494 | 0.734651 | 0.734651
Apartamento 1 - Parede-005 | Parede-externa-inloco-bloco_concreto-estrutural-19cm | yes | yes | 1035.68 (kgCO₂) | 10043 | 6187.33 | 2400 | 1.17559 | 14.8496 | 11.9696 | 2.82142 | 2.27422 | 5230.72 | 11.9696 | 14.8496 | 14.8496 | 2600 | 0.494 | 2.27422 | 2.82142
Apartamento 1 - Parede-001 | Parede-externa-inloco-bloco_concreto-estrutural-19cm | yes | yes | 1317.64 (kgCO₂) | 12777.1 | 8584.77 | 2400 | 1.47911 | 20.6034 | 15.2194 | 3.91465 | 2.89337 | 6654.76 | 15.2434 | 20.6034 | 18.2034 | 2600 | 0.494 | 2.89337 | 3.91465
Apartamento 1 - Parede-001 | Parede-externa-inloco-bloco_concreto-estrutural-19cm | yes | yes | 1038.31 (kgCO₂) | 10068.5 | 4905 | 2400 | 0.95 | 12 | 12 | 2.28 | 2.28 | 5243.99 | 12 | 12 | 12 | 2600 | 0.494 | 2.27999 | 2.27999
Apartamento 1 - Parede-007 | Parede-interna-inloco-bloco_concreto-estrutural-19cm | no | yes | 994.275 (kgCO₂) | 9641.46 | 6195.39 | 2600 | 0.871588 | 14.8511 | 11.4911 | 2.8217 | 2.1833 | 5021.59 | 11.4912 | 14.8512 | 14.8512 | 2600 | 0.494 | 2.1833 | 2.8217
Apartamento 1 - Parede-008 | Parede-interna-inloco-bloco_concreto-estrutural-19cm | no | yes | 267.884 (kgCO₂) | 2597.67 | 1920 | 2400 | 0.2261 | 4.776 | 3.096 | 0.90744 | 0.58824 | 1352.95 | 3.096 | 4.776 | 4.776 | 2600 | 0.494 | 0.58824 | 0.90744
Apartamento 1 - Parede-009 | Parede-interna-inloco-bloco_concreto-estrutural-19cm | no | yes | 417.401 (kgCO₂) | 4047.53 | 2010 | 2400 | 0.3819 | 4.824 | 4.824 | 0.91656 | 0.91656 | 2108.09 | 4.824 | 4.824 | 4.824 | 2600 | 0.494 | 0.91656 | 0.91656
Apartamento 1 - Parede-004 | Parede-externa-inloco-bloco_concreto-estrutural-19cm | yes | yes | 293.607 (kgCO₂) | 2847.1 | 1412.86 | 2600 | 0.268443 | 3.53213 | 3.53213 | 0.644723 | 0.644723 | 1482.86 | 3.67341 | 3.67341 | 3.67341 | 2600 | 0.494 | 0.644723 | 0.644723
Apartamentos 1 e 2 - Parede-006 | Parede-interna-inloco-bloco_concreto-estrutural-19cm | no | yes | 1410.63 (kgCO₂) | 13678.8 | 6792.9 | 2400 | 1.29065 | 16.303 | 16.303 | 3.09756 | 3.09756 | 7124.4 | 16.303 | 16.303 | 16.303 | 2600 | 0.494 | 3.09756 | 3.09756
Apartamento 2 - Parede-003 | Parede-externa-inloco-bloco_concreto-estrutural-19cm | yes | yes | 427.772 (kgCO₂) | 4148.1 | 2397.46 | 2600 | 0.455517 | 5.7546 | 4.9426 | 1.09337 | 0.939333 | 2160.47 | 4.95464 | 5.75464 | 5.75464 | 2600 | 0.494 | 0.939333 | 1.09337
Apartamento 2 - Parede-078 | Parede-interna-inloco-bloco_concreto-estrutural-19cm | no | yes | 334.56 (kgCO₂) | 3244.22 | 1702.17 | 2600 | 0.305362 | 4.01792 | 4.01792 | 0.73465 | 0.734651 | 1689.7 | 4.17872 | 4.17872 | 4.17872 | 2600 | 0.494 | 0.734651 | 0.734651
Apartamento 2 - Parede-005 | Parede-externa-inloco-bloco_concreto-estrutural-19cm | yes | yes | 1035.68 (kgCO₂) | 10043 | 6187.33 | 2400 | 1.17559 | 14.8496 | 11.9696 | 2.82142 | 2.27422 | 5230.72 | 11.9696 | 14.8496 | 14.8496 | 2600 | 0.494 | 2.27422 | 2.82142
Apartamento 2 - Parede-001 | Parede-externa-inloco-bloco_concreto-estrutural-19cm | yes | yes | 1317.64 (kgCO₂) | 12777.1 | 8584.77 | 2400 | 1.47911 | 20.6034 | 15.2194 | 3.91465 | 2.89337 | 6654.76 | 15.2434 | 20.6034 | 18.2034 | 2600 | 0.494 | 2.89337 | 3.91465
Apartamento 2 - Parede-001 | Parede-externa-inloco-bloco_concreto-estrutural-19cm | yes | yes | 1038.31 (kgCO₂) | 10068.5 | 4905 | 2400 | 0.95 | 12 | 12 | 2.28 | 2.28 | 5243.99 | 12 | 12 | 12 | 2600 | 0.494 | 2.27999 | 2.27999
Apartamento 2 - Parede-007 | Parede-interna-inloco-bloco_concreto-estrutural-19cm | no | yes | 995.955 (kgCO₂) | 9657.74 | 6195.39 | 2600 | 0.873124 | 14.8705 | 11.5105 | 2.82539 | 2.18699 | 5030.07 | 11.5105 | 14.8705 | 14.8705 | 2600 | 0.494 | 2.18699 | 2.82539
Apartamento 2 - Parede-008 | Parede-interna-inloco-bloco_concreto-estrutural-19cm | no | yes | 267.884 (kgCO₂) | 2597.67 | 1920 | 2400 | 0.2261 | 4.776 | 3.096 | 0.90744 | 0.58824 | 1352.95 | 3.096 | 4.776 | 4.776 | 2600 | 0.494 | 0.58824 | 0.90744
Apartamento 2 - Parede-009 | Parede-interna-inloco-bloco_concreto-estrutural-19cm | no | yes | 417.401 (kgCO₂) | 4047.53 | 2010 | 2400 | 0.3819 | 4.824 | 4.824 | 0.91656 | 0.91656 | 2108.09 | 4.824 | 4.824 | 4.824 | 2600 | 0.494 | 0.91656 | 0.91656
Apartamento 2 - Parede-004 | Parede-externa-inloco-bloco_concreto-estrutural-19cm | yes | yes | 293.607 (kgCO₂) | 2847.1 | 1412.86 | 2600 | 0.268443 | 3.53213 | 3.53213 | 0.644723 | 0.644723 | 1482.86 | 3.6734 | 3.6734 | 3.6734 | 2600 | 0.494 | 0.644723 | 0.644723
Apartamento 3 - Parede-003 | Parede-externa-inloco-bloco_concreto-estrutural-19cm | yes | yes | 427.772 (kgCO₂) | 4148.1 | 2397.46 | 2600 | 0.455517 | 5.7546 | 4.9426 | 1.09337 | 0.939334 | 2160.47 | 4.95464 | 5.75464 | 5.75464 | 2600 | 0.494 | 0.939333 | 1.09337
Apartamento 3 - Parede-005 | Parede-externa-inloco-bloco_concreto-estrutural-19cm | yes | yes | 1035.68 (kgCO₂) | 10043 | 6187.33 | 2400 | 1.17559 | 14.8496 | 11.9696 | 2.82142 | 2.27422 | 5230.72 | 11.9696 | 14.8496 | 14.8496 | 2600 | 0.494 | 2.27422 | 2.82142
Apartamento 3 - Parede-078 | Parede-interna-inloco-bloco_concreto-estrutural-19cm | no | yes | 334.56 (kgCO₂) | 3244.22 | 1702.17 | 2600 | 0.305362 | 4.01792 | 4.01792 | 0.73465 | 0.734651 | 1689.7 | 4.17871 | 4.17871 | 4.17871 | 2600 | 0.494 | 0.734651 | 0.734651
Apartamento 3 - Parede-001 | Parede-externa-inloco-bloco_concreto-estrutural-19cm | yes | yes | 1317.64 (kgCO₂) | 12777.1 | 8584.77 | 2400 | 1.47911 | 20.6034 | 15.2194 | 3.91465 | 2.89337 | 6654.76 | 15.2434 | 20.6034 | 18.2034 | 2600 | 0.494 | 2.89337 | 3.91465
Apartamento 3 - Parede-001 | Parede-externa-inloco-bloco_concreto-estrutural-19cm | yes | yes | 1038.31 (kgCO₂) | 10068.5 | 4905 | 2400 | 0.95 | 12 | 12 | 2.28 | 2.28 | 5243.99 | 12 | 12 | 12 | 2600 | 0.494 | 2.27999 | 2.27999
Apartamento 3 - Parede-007 | Parede-interna-inloco-bloco_concreto-estrutural-19cm | no | yes | 994.275 (kgCO₂) | 9641.46 | 6195.39 | 2600 | 0.871588 | 14.8511 | 11.4911 | 2.8217 | 2.1833 | 5021.59 | 11.4912 | 14.8512 | 14.8512 | 2600 | 0.494 | 2.1833 | 2.8217
Apartamento 3 - Parede-008 | Parede-interna-inloco-bloco_concreto-estrutural-19cm | no | yes | 267.884 (kgCO₂) | 2597.67 | 1920 | 2400 | 0.2261 | 4.776 | 3.096 | 0.90744 | 0.58824 | 1352.95 | 3.096 | 4.776 | 4.776 | 2600 | 0.494 | 0.58824 | 0.90744
Apartamento 3 - Parede-009 | Parede-interna-inloco-bloco_concreto-estrutural-19cm | no | yes | 417.401 (kgCO₂) | 4047.53 | 2010 | 2400 | 0.3819 | 4.824 | 4.824 | 0.91656 | 0.91656 | 2108.09 | 4.824 | 4.824 | 4.824 | 2600 | 0.494 | 0.91656 | 0.91656
Apartamento 3 - Parede-004 | Parede-externa-inloco-bloco_concreto-estrutural-19cm | yes | yes | 293.607 (kgCO₂) | 2847.1 | 1412.86 | 2600 | 0.268443 | 3.53213 | 3.53213 | 0.644723 | 0.644723 | 1482.86 | 3.67341 | 3.67341 | 3.67341 | 2600 | 0.494 | 0.644723 | 0.644723
Apartamentos 3 e 4 - Parede-006 | Parede-interna-inloco-bloco_concreto-estrutural-19cm | no | yes | 1410.63 (kgCO₂) | 13678.8 | 6792.9 | 2400 | 1.29065 | 16.303 | 16.303 | 3.09756 | 3.09756 | 7124.4 | 16.303 | 16.303 | 16.303 | 2600 | 0.494 | 3.09756 | 3.09756
Apartamento 4 - Parede-003 | Parede-externa-inloco-bloco_concreto-estrutural-19cm | yes | yes | 427.772 (kgCO₂) | 4148.1 | 2397.46 | 2600 | 0.455517 | 5.7546 | 4.9426 | 1.09337 | 0.939333 | 2160.47 | 4.95464 | 5.75464 | 5.75464 | 2600 | 0.494 | 0.939333 | 1.09337
Apartamento 4 - Parede-078 | Parede-interna-inloco-bloco_concreto-estrutural-19cm | no | yes | 334.56 (kgCO₂) | 3244.22 | 1702.17 | 2600 | 0.305362 | 4.01792 | 4.01792 | 0.73465 | 0.734651 | 1689.7 | 4.17872 | 4.17872 | 4.17872 | 2600 | 0.494 | 0.734651 | 0.734651
Apartamento 4 - Parede-005 | Parede-externa-inloco-bloco_concreto-estrutural-19cm | yes | yes | 1035.68 (kgCO₂) | 10043 | 6187.33 | 2400 | 1.17559 | 14.8496 | 11.9696 | 2.82142 | 2.27422 | 5230.72 | 11.9696 | 14.8496 | 14.8496 | 2600 | 0.494 | 2.27422 | 2.82142
Apartamento 4 - Parede-001 | Parede-externa-inloco-bloco_concreto-estrutural-19cm | yes | yes | 1317.64 (kgCO₂) | 12777.1 | 8584.77 | 2400 | 1.47911 | 20.6034 | 15.2194 | 3.91465 | 2.89337 | 6654.76 | 15.2434 | 20.6034 | 18.2034 | 2600 | 0.494 | 2.89337 | 3.91465
Apartamento 4 - Parede-001 | Parede-externa-inloco-bloco_concreto-estrutural-19cm | yes | yes | 1038.31 (kgCO₂) | 10068.5 | 4905 | 2400 | 0.95 | 12 | 12 | 2.28 | 2.28 | 5243.99 | 12 | 12 | 12 | 2600 | 0.494 | 2.27999 | 2.27999
Apartamento 4 - Parede-007 | Parede-interna-inloco-bloco_concreto-estrutural-19cm | no | yes | 995.955 (kgCO₂) | 9657.74 | 6195.39 | 2600 | 0.873124 | 14.8705 | 11.5105 | 2.82539 | 2.18699 | 5030.07 | 11.5105 | 14.8705 | 14.8705 | 2600 | 0.494 | 2.18699 | 2.82539
Apartamento 4 - Parede-008 | Parede-interna-inloco-bloco_concreto-estrutural-19cm | no | yes | 267.884 (kgCO₂) | 2597.67 | 1920 | 2400 | 0.2261 | 4.776 | 3.096 | 0.90744 | 0.58824 | 1352.95 | 3.096 | 4.776 | 4.776 | 2600 | 0.494 | 0.58824 | 0.90744
Apartamento 4 - Parede-009 | Parede-interna-inloco-bloco_concreto-estrutural-19cm | no | yes | 417.401 (kgCO₂) | 4047.53 | 2010 | 2400 | 0.3819 | 4.824 | 4.824 | 0.91656 | 0.91656 | 2108.09 | 4.824 | 4.824 | 4.824 | 2600 | 0.494 | 0.91656 | 0.91656
Apartamento 4 - Parede-004 | Parede-externa-inloco-bloco_concreto-estrutural-19cm | yes | yes | 293.607 (kgCO₂) | 2847.1 | 1412.86 | 2600 | 0.268443 | 3.53213 | 3.53213 | 0.644723 | 0.644723 | 1482.86 | 3.6734 | 3.6734 | 3.6734 | 2600 | 0.494 | 0.644723 | 0.644723
2 x NúcleoParede-003 | Parede-externa-inloco-bloco_concreto-estrutural-19cm |  |  | 748.623 (kgCO₂) | 7259.37 | 7210 | 1200 | 1.3699 | 8.652 | 8.652 | 1.64388 | 1.64388 | 3780.92 | 8.652 | 8.652 | 8.652 | 1200 | 0.228 | 1.64388 | 1.64388

# IfcWallStandardCase: Concreto 140 (16)
In: Pavimento Tipo
Description: Parede-interna-inloco-bloco_concreto-14cm; Classification: 3E 14 02 00 Parede (NBR 15965-5 3E); Parede (Classificação Archicad); Material: Concreto 140 mm
Pset_WallCommon - AcousticRating: 0,00; IsExternal: no; LoadBearing: no
Component Properties - Concreto, Tipo de Componente: Nenhum
AC_Pset_RenovationAndPhasing - Renovation Status: Existing
Component Quantities - Concreto, Espessura do Componente: 140 mm; Concreto, Altura do Componente Retangular: 2600 mm; Concreto, Largura do Componente Retangular: 140 mm; Concreto, Área de Seção Transversal do Componente: 0.364 m2
BaseQuantities - Height: 2600 mm; Width: 140 mm
Name | Concreto, Carbono Incorporado | Concreto, Energia Incorporada (MJ) | Concreto, Massa (kg) | Concreto, Área de Componente Projetada (Líquida) (m2) = Concreto, Área de Componente Projetada (Bruta) (m2) = Concreto, Área de Componente Projetada (Condicional) (m2) | Concreto, Volume Componente (Líquido) (m3) = Concreto, Volume do componente (Bruto) (m3) = Concreto, Volume Componente (Condicional) (m3) = GrossVolume (m3) = NetVolume (m3) | Length (mm) | GrossFootprintArea (m2) = NetFootprintArea (m2) | GrossSideArea (m2) = NetSideArea (m2)
Apartamento 1 - Parede-010 | 140.914 (kgCO₂) | 974.544 | 1316.95 | 5.226 | 0.73164 | 2105 | 0.2814 | 5.226
Apartamento 1 - Parede-012 | 46.2702 (kgCO₂) | 320 | 432.432 | 1.716 | 0.24024 | 660 | 0.0924 | 1.716
Apartamento 1 - Parede-060 | 225.117 (kgCO₂) | 1556.88 | 2103.89 | 8.34884 | 1.16883 | 3211.07 | 0.44955 | 8.34878
Apartamento 1 - Parede-011 | 28.0426 (kgCO₂) | 193.939 | 262.08 | 1.04 | 0.1456 | 400 | 0.056 | 1.04
Apartamento 2 - Parede-010 | 140.914 (kgCO₂) | 974.544 | 1316.95 | 5.226 | 0.73164 | 2105 | 0.2814 | 5.226
Apartamento 2 - Parede-012 | 46.2702 (kgCO₂) | 320 | 432.432 | 1.716 | 0.24024 | 660 | 0.0924 | 1.716
Apartamento 2 - Parede-011 | 28.0426 (kgCO₂) | 193.939 | 262.08 | 1.04 | 0.1456 | 400 | 0.056 | 1.04
Apartamento 2 - Parede-060 | 225.117 (kgCO₂) | 1556.88 | 2103.89 | 8.34884 | 1.16883 | 3211.07 | 0.44955 | 8.34878
Apartamento 3 - Parede-010 | 140.914 (kgCO₂) | 974.544 | 1316.95 | 5.226 | 0.73164 | 2105 | 0.2814 | 5.226
Apartamento 3 - Parede-012 | 46.2702 (kgCO₂) | 320 | 432.432 | 1.716 | 0.24024 | 660 | 0.0924 | 1.716
Apartamento 3 - Parede-060 | 225.117 (kgCO₂) | 1556.88 | 2103.89 | 8.34884 | 1.16883 | 3211.07 | 0.44955 | 8.34878
Apartamento 3 - Parede-011 | 28.0426 (kgCO₂) | 193.939 | 262.08 | 1.04 | 0.1456 | 400 | 0.056 | 1.04
Apartamento 4 - Parede-010 | 140.914 (kgCO₂) | 974.544 | 1316.95 | 5.226 | 0.73164 | 2105 | 0.2814 | 5.226
Apartamento 4 - Parede-012 | 46.2702 (kgCO₂) | 320 | 432.432 | 1.716 | 0.24024 | 660 | 0.0924 | 1.716
Apartamento 4 - Parede-011 | 28.0426 (kgCO₂) | 193.939 | 262.08 | 1.04 | 0.1456 | 400 | 0.056 | 1.04
Apartamento 4 - Parede-060 | 225.117 (kgCO₂) | 1556.88 | 2103.89 | 8.34884 | 1.16883 | 3211.07 | 0.44955 | 8.34878

# IfcWindow: Janela 27 (4)
In: Pavimento Tipo
Type - OperationType: SINGLE_PANEL; ParameterTakesPrecedence: no; Sizeable: no
Type - Window Lining Properties - LiningDepth: 50 mm; LiningThickness: 47 mm
Type - Window Panel Properties - Panel 1 - OperationType: TOPHUNG; PanelPosition: MIDDLE; FrameDepth: 20 mm; FrameThickness: 50 mm
Description: Janela-externa-genérico-alumínio-maxim_ar-80cm x 60cm; OverallHeight: 600 mm; OverallWidth: 800 mm; Classification: 3E 20 04 02 06 Janela basculante (NBR 15965-5 3E); Janela (Classificação Archicad)
Pset_WindowCommon - ThermalTransmittance: 0
BaseQuantities - GrossArea: 0.48 m2; Height: 600 mm; Width: 800 mm; Perimeter: 2800 mm; Area: 0.48 m2; Volume: 0.0253701 m3; Depth: 190 mm; NetVolume: 0.0253701 m3
Component Quantities - Component, Volume Componente (Líquido): 0.0253701 m3; Component, Volume do componente (Bruto): 0.0253701 m3
AC_Pset_RenovationAndPhasing - Renovation Status: Existing
Name
Apartamento 1 - J02
Apartamento 2 - J02
Apartamento 3 - J02
Apartamento 4 - J02

# IfcWindow: Janela Multi-Caixilho Vertical 27 (8)
In: Pavimento Tipo
Type - OperationType: USERDEFINED; ParameterTakesPrecedence: no; Sizeable: no
Description: Janela-externa-genérico-alumínio-basculante-80cm x 100cm; OverallHeight: 1000 mm; OverallWidth: 800 mm; Classification: 3E 20 04 02 06 Janela basculante (NBR 15965-5 3E); Janela (Classificação Archicad)
Pset_WindowCommon - ThermalTransmittance: 0
AC_Pset_RenovationAndPhasing - Renovation Status: Existing
Component Quantities - Component, Volume Componente (Líquido): 0.0194095 m3; Component, Volume do componente (Bruto): 0.0194095 m3
BaseQuantities - GrossArea: 0.8 m2; Height: 1000 mm; Width: 800 mm; Perimeter: 3600 mm; Area: 0.8 m2; Volume: 0.0194095 m3; Depth: 190 mm; NetVolume: 0.0194095 m3
Name
Apartamento 1 - J04
Apartamento 1 - J03
Apartamento 2 - J04
Apartamento 2 - J03
Apartamento 3 - J04
Apartamento 3 - J03
Apartamento 4 - J04
Apartamento 4 - J03

# IfcWindow: Janela de Correr 4-Folhas 27 (12)
In: Pavimento Tipo
Type - OperationType: USERDEFINED; ParameterTakesPrecedence: no; Sizeable: no
OverallHeight: 1200 mm; Classification: Janela (Classificação Archicad); 3E 20 04 02 02 Janela de correr (NBR 15965-5 3E)
Pset_WindowCommon - ThermalTransmittance: 0
AC_Pset_RenovationAndPhasing - Renovation Status: Existing
BaseQuantities - Height: 1200 mm; Depth: 190 mm
Name | Description | OverallWidth (mm) = Width (mm) | Component, Volume Componente (Líquido) (m3) = Component, Volume do componente (Bruto) (m3) = Volume (m3) = NetVolume (m3) | GrossArea (m2) = Area (m2) | Perimeter (mm)
Apartamento 1 - J06 | Janela-externa-genérico-alumínio-correr-120cm x 120cm | 1200 | 0.049487 | 1.44 | 4800
Apartamento 1 - J05 | Janela-externa-genérico-alumínio-correr-120cm x 120cm | 1200 | 0.049487 | 1.44 | 4800
Apartamento 1 - J01 | Janela-externa-genérico-alumínio-correr-160cm x 120cm | 2000 | 0.0645128 | 2.4 | 6400
Apartamento 2 - J05 | Janela-externa-genérico-alumínio-correr-120cm x 120cm | 1200 | 0.049487 | 1.44 | 4800
Apartamento 2 - J06 | Janela-externa-genérico-alumínio-correr-120cm x 120cm | 1200 | 0.049487 | 1.44 | 4800
Apartamento 2 - J01 | Janela-externa-genérico-alumínio-correr-160cm x 120cm | 2000 | 0.0645128 | 2.4 | 6400
Apartamento 3 - J05 | Janela-externa-genérico-alumínio-correr-120cm x 120cm | 1200 | 0.049487 | 1.44 | 4800
Apartamento 3 - J06 | Janela-externa-genérico-alumínio-correr-120cm x 120cm | 1200 | 0.049487 | 1.44 | 4800
Apartamento 3 - J01 | Janela-externa-genérico-alumínio-correr-160cm x 120cm | 2000 | 0.0645128 | 2.4 | 6400
Apartamento 4 - J06 | Janela-externa-genérico-alumínio-correr-120cm x 120cm | 1200 | 0.049487 | 1.44 | 4800
Apartamento 4 - J05 | Janela-externa-genérico-alumínio-correr-120cm x 120cm | 1200 | 0.049487 | 1.44 | 4800
Apartamento 4 - J01 | Janela-externa-genérico-alumínio-correr-160cm x 120cm | 2000 | 0.0645128 | 2.4 | 6400
